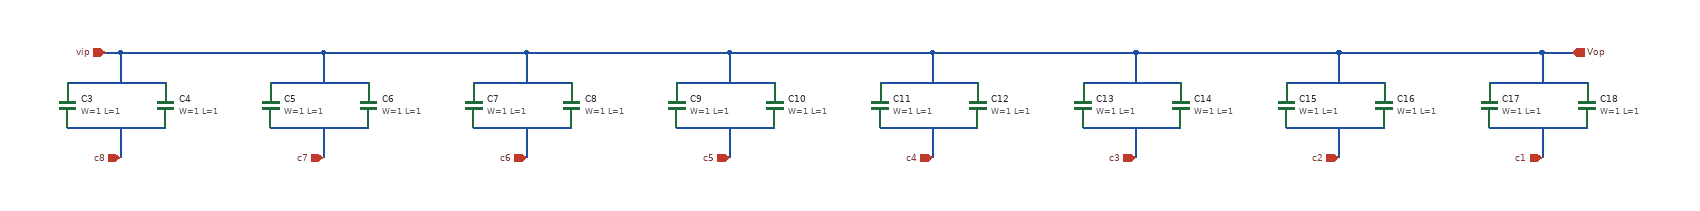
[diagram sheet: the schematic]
v {xschem version=3.4.8RC file_version=1.2}
G {}
K {}
V {}
S {}
E {}
N 250 -30 380 -30 {lab=Vop}
N 320 -70 320 -30 {lab=Vop}
N 320 -70 590 -70 {lab=Vop}
N 520 -30 650 -30 {lab=Vop}
N 590 -70 590 -30 {lab=Vop}
N 790 -30 920 -30 {lab=Vop}
N 860 -70 860 -30 {lab=Vop}
N 590 -70 860 -70 {lab=Vop}
N 860 -70 1130 -70 {lab=Vop}
N 1060 -30 1190 -30 {lab=Vop}
N 1130 -70 1130 -30 {lab=Vop}
N 1330 -30 1460 -30 {lab=Vop}
N 1400 -70 1400 -30 {lab=Vop}
N 1130 -70 1400 -70 {lab=Vop}
N 1400 -70 1670 -70 {lab=Vop}
N 1600 -30 1730 -30 {lab=Vop}
N 1670 -70 1670 -30 {lab=Vop}
N 1870 -30 2000 -30 {lab=Vop}
N 1870 30 2000 30 {lab=c2}
N 1940 -70 1940 -30 {lab=Vop}
N 1670 -70 1940 -70 {lab=Vop}
N 1600 30 1730 30 {lab=c3}
N 1330 30 1460 30 {lab=c4}
N 1060 30 1190 30 {lab=c5}
N 790 30 920 30 {lab=c6}
N 520 30 650 30 {lab=c7}
N 250 30 380 30 {lab=c8}
N 300 -70 320 -70 {lab=Vop}
N 1940 -70 2210 -70 {lab=Vop}
N 2140 -30 2270 -30 {lab=Vop}
N 2140 30 2270 30 {lab=c8}
N 2210 -70 2210 -30 {lab=Vop}
N 2210 -70 2250 -70 {lab=Vop}
N 320 30 320 70 {lab=c8}
N 590 30 590 70 {lab=c7}
N 860 30 860 70 {lab=c6}
N 1130 30 1130 70 {lab=c5}
N 1400 30 1400 70 {lab=c4}
N 1670 30 1670 70 {lab=c3}
N 1940 30 1940 70 {lab=c2}
N 2210 30 2210 70 {lab=c8}
C {sky130_fd_pr/cap_mim_m3_1.sym} 250 0 0 0 {name=C3 model=cap_mim_m3_1 W=1 L=1 MF=64 spiceprefix=X}
C {sky130_fd_pr/cap_mim_m3_1.sym} 380 0 0 0 {name=C4 model=cap_mim_m3_1 W=1 L=1 MF=64 spiceprefix=X}
C {sky130_fd_pr/cap_mim_m3_1.sym} 520 0 0 0 {name=C5 model=cap_mim_m3_1 W=1 L=1 MF=32 spiceprefix=X}
C {sky130_fd_pr/cap_mim_m3_1.sym} 650 0 0 0 {name=C6 model=cap_mim_m3_1 W=1 L=1 MF=32 spiceprefix=X}
C {sky130_fd_pr/cap_mim_m3_1.sym} 790 0 0 0 {name=C7 model=cap_mim_m3_1 W=1 L=1 MF=16 spiceprefix=X}
C {sky130_fd_pr/cap_mim_m3_1.sym} 920 0 0 0 {name=C8 model=cap_mim_m3_1 W=1 L=1 MF=16 spiceprefix=X}
C {sky130_fd_pr/cap_mim_m3_1.sym} 1060 0 0 0 {name=C9 model=cap_mim_m3_1 W=1 L=1 MF=8 spiceprefix=X}
C {sky130_fd_pr/cap_mim_m3_1.sym} 1190 0 0 0 {name=C10 model=cap_mim_m3_1 W=1 L=1 MF=8 spiceprefix=X}
C {sky130_fd_pr/cap_mim_m3_1.sym} 1330 0 0 0 {name=C11 model=cap_mim_m3_1 W=1 L=1 MF=4 spiceprefix=X}
C {sky130_fd_pr/cap_mim_m3_1.sym} 1460 0 0 0 {name=C12 model=cap_mim_m3_1 W=1 L=1 MF=4 spiceprefix=X}
C {sky130_fd_pr/cap_mim_m3_1.sym} 1600 0 0 0 {name=C13 model=cap_mim_m3_1 W=1 L=1 MF=2 spiceprefix=X}
C {sky130_fd_pr/cap_mim_m3_1.sym} 1730 0 0 0 {name=C14 model=cap_mim_m3_1 W=1 L=1 MF=2 spiceprefix=X}
C {sky130_fd_pr/cap_mim_m3_1.sym} 1870 0 0 0 {name=C15 model=cap_mim_m3_1 W=1 L=1 MF=1 spiceprefix=X}
C {sky130_fd_pr/cap_mim_m3_1.sym} 2000 0 0 0 {name=C16 model=cap_mim_m3_1 W=1 L=1 MF=1 spiceprefix=X}
C {opin.sym} 2250 -70 0 0 {name=p7 lab=Vop}
C {ipin.sym} 300 -70 0 0 {name=p1 lab=vip}
C {sky130_fd_pr/cap_mim_m3_1.sym} 2140 0 0 0 {name=C17 model=cap_mim_m3_1 W=1 L=1 MF=1 spiceprefix=X}
C {sky130_fd_pr/cap_mim_m3_1.sym} 2270 0 0 0 {name=C18 model=cap_mim_m3_1 W=1 L=1 MF=1 spiceprefix=X}
C {iopin.sym} 320 70 0 0 {name=p2 lab=c8}
C {iopin.sym} 590 70 0 0 {name=p3 lab=c7}
C {iopin.sym} 860 70 0 0 {name=p4 lab=c6}
C {iopin.sym} 1130 70 0 0 {name=p5 lab=c5}
C {iopin.sym} 1400 70 0 0 {name=p6 lab=c4}
C {iopin.sym} 1670 70 0 0 {name=p8 lab=c3}
C {iopin.sym} 1940 70 0 0 {name=p9 lab=c2}
C {iopin.sym} 2210 70 0 0 {name=p10 lab=c1}
